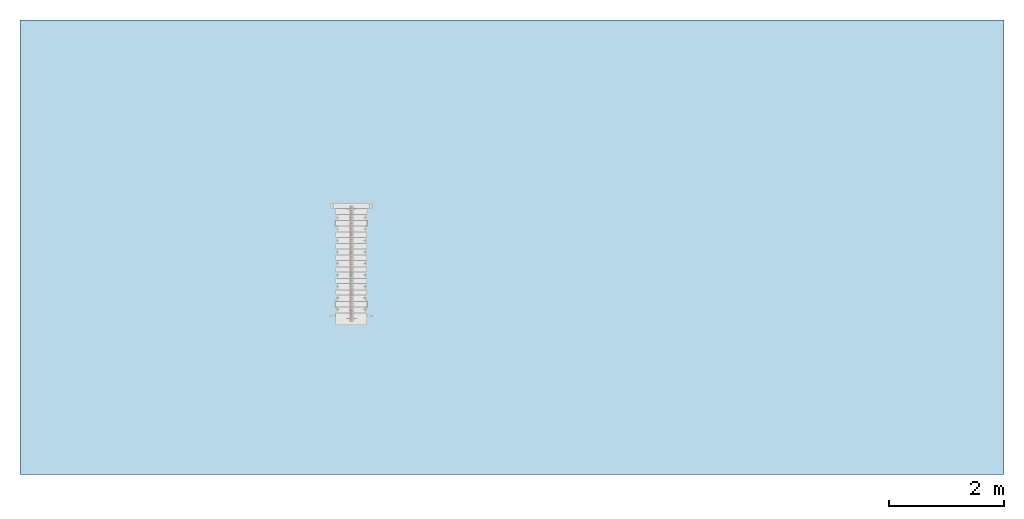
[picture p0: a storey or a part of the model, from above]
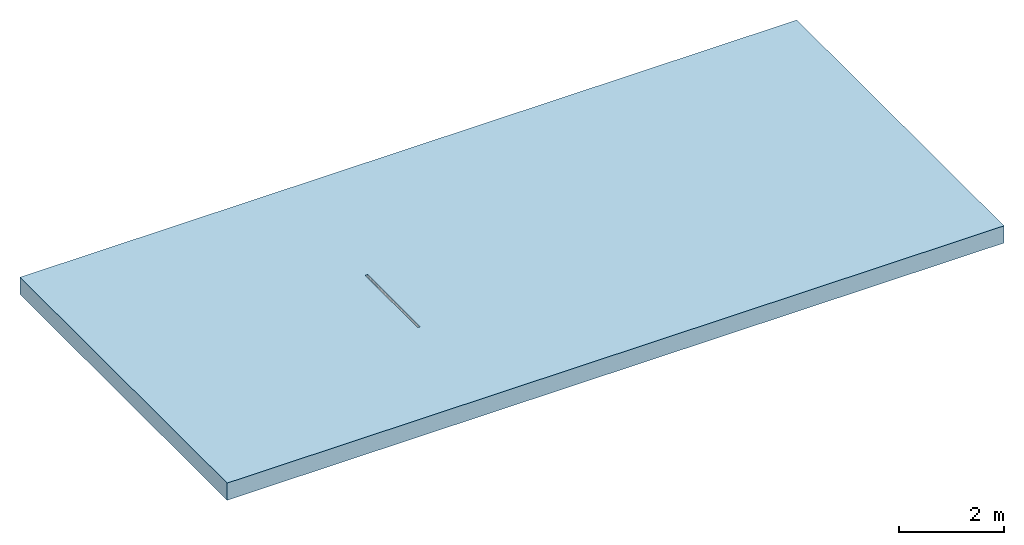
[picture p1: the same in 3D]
Properties of the parts of a building model (IFC2X3)

# File
Description: ViewDefinition [CoordinationView]
File name: 32833 - Q-Guard Edge - G.S.ifc
Time: 2013-07-11T16:58:51
Written by: Autodesk Revit 2013
Made in: 20120221_2030(x64)

# IfcProject, Project Number
LongName: Project Name; Phase: Project Status

# IfcSite, Default
RefLatitude: 42, 21, 30, 344238; RefLongitude: -71, -3, -35, -194702; RefElevation: 0 mm

# IfcBuilding
Pset_BuildingCommon - NumberOfStoreys: 1
Other - Project Name: Project Name; Project Number: Project Number; Client Name: Owner; Project Issue Date: Issue Date; Project Status: Project Status; Project Address: ## Street City, State Zip

# IfcBuildingStorey, Level 1
LongName: Level 1; Elevation: 0 mm
Constraints - Elevation Base: 0; Elevation: 0 mm
Graphics - Color: 0; Symbol at End 1 Default: no; Line Pattern: Center; Symbol at End 2 Default: yes; Symbol: M_Level Head - Circle: M_Level Head - Circle; Line Weight: 1
Dimensions - Computation Height: 0 mm
Identity Data - Structural: no; Name: Level 1; Building Story: yes

# IfcFlowTerminal: 32833 - Q-Guard Edge - G.S, Qmax 700:32833 - Q-Guard Edge - G.S:32833 - Q-Guard Edge - G.S:502881
In: Level 1
Construction - 32854_Chamber connector (at Female end): no; 32882_550-700 Step Connector: no; 32835_Closing End cap (at Female end): no; 32854_Chamber connector (at Male end): no; 32835_Closing End cap (at Male end): yes; E5-QSlot-GalvSteel: no; E3-QFlow-GalvSteel: no; E1-QFlow-DuctileIron: no; E4-QGuard-GalvSteel: yes; E2-QGuard-DuctileIron: no; V_CoarseE1: yes; V_Coarse_E5: no
Identity Data - Mark: 37; Product Brochure: http://www.aco.co.uk/download.php?id=220; URL: www.aco.co.uk; Installation Guidelines: http://www.aco.co.uk/download.php?id=220; Assembly Description: Rain Water Drainage; Type Comments: ACO Qmax 700 channel assembly complete with ACO Q-Guard galvanised steel edge rail; Manufacturer: ACO Technologies plc - ACO Water Management Division; Fax: +44 (0)1462 815895; Maintenance Guidelines: http://www.aco.co.uk/download.php?id=220; e-mail Sales: customersupport@aco.co.uk; Product Page URL: http://www.aco.co.uk/product_detail.php?id=79; OmniClass Title: Rainwater Removal; Model Description: High capacity slot drainage channel system; Cost: 0; Price: POA - contact ACO; Product Code: 32833; Assembly Code: D2040; Address: ACO Business Park, Hitchin Road, Shefford, Bedfordshire, United Kingdom SG17 5TE; OmniClass Number: 23.70.50.24; Model: ACO Qmax 700; e-mail Technical: technical@aco.co.uk; Telephone: +44 (0)1462 816666
Constraints - Moves With Nearby Elements: no; Level: Level: Level 1
Phasing - Phase Created: New Construction
General - TagNumber: 0; SerialNumber: 0
Data - Installation - Reinforcement Details: Refer to brochure; Concrete Surround Volume - Load Class A 15 - D 400: 0.56 m³/m; Concrete Surround Volume - Load Class E 600 - F 900: 0.72 m³/m; Channel C.S.A: 249703mm²; Load Class: A 15 - F 900; ACO Hydraulic Design Software: http://www.acodesign.co.uk; Product Weight: 39.4 kg; Drainage Slot Width: 10mm; Invert Depth: 950mm; Hydraulic Performance: http://www.aco.co.uk/download.php?id=220; Product Standard: BS EN 1433:2002 CE marked; Installation - Concrete Grade: Refer to brochure; Drainage Slot Intake Area: 8356mm²/m; Product Dimensions: 2000mm x 730mm x 1070mm (LxWxH)
Model Properties - 550-700 Step Connector Product Code: 32882; 550-700 Step Connector Weight: 2.5 kg; Chamber Connector Channel Colour: Black; Chamber Connector Model Description: High capacity slot drainage channel system; Closing End Cap Dimensions: 730mm x 12mm x 865mm (LxWxH); Chamber Connector Product Code: 32854; Closing End Cap Material: High Density Polyethylene; 550-700 Step Connector Recyclable: Fully recyclable; Closing End Cap Recycled Material Content: 0%; Chamber Connector Weight: 15.8 kg; Closing End Cap Product Code: 32835; 550-700 Step Connector Recycled Material Content: 0%; Chamber Connector Dimensions: Female End=800mm x 715mm x 895mm, Male End=800mm x 715mm x 845mm (LxWxH); 550-700 Step Connector Model Description: High capacity slot drainage channel system; Closing End Cap Colour: Black; 550-700 Step Connector Material: High Density Polyethylene; Closing End Cap Weight: 4.9 kg; Chamber Connector Recycled Material Content: Variable %; Chamber Connector Recyclable: Fully recyclable; Chamber Connector Channel Material: Medium Density Polyethylene; 550-700 Step Connector Colour: Black; Closing End Cap Recyclable: Fully recyclable; Closing End Cap Model Description: High capacity slot drainage channel system; 550-700 Step Connector Dimensions: 730mm x 45mm x 865mm (LxWxH)
Materials and Finishes - Edge Rail Finish: Galvanised; Channel Colour: Black; Seal Material: EPDM; Edge Rail Colour: Silver; Channel Material: Medium Density Polyethylene; Edge Rail Material: Steel; Seal Colour: Black
Green Building Properties - Channel Recycled Material Content: Variable %; Channel Recyclable: Fully recyclable; Seal Recyclable: Fully recyclable; Edge Rail Recycled Material Content: Between 40% - 90%; Edge Rail Recyclable: Fully recyclable; Seal Recycled Material Content: 0%
Dimensions - StepConn-Origin: 580.3 mm; ClosingEndCapOrigin: 570.2 mm; ChamberOrigin: 480 mm; Floor Opening Width: 55 mm; Length: 2000 mm; Depth Overall: 1070 mm; Width Overall: 730 mm
Other - Revision: 1; Created by: www.aco.co.uk

# IfcOpeningElement: Opening
In: Level 1
Constraints - Height Offset From Level: 0 mm; Level: Level: Level 1; Room Bounding: yes; Related to Mass: no
Dimensions - Perimeter: 50000 mm; Thickness: 400 mm; Volume: 53488000000 mm3; Area: 134980000 mm2
Phasing - Phase Created: New Construction
Structural - Enable Analytical Model: no; Structural: no
Graphics - Coarse Scale Fill Color: 0
Analytical Properties - Absorptance: 0.1; Roughness: 1
Construction - Default Thickness: 400 mm; Function: 0
Materials and Finishes - Structural Material: Plant

# IfcSlab: Floor:Generic Floor - 400mm, Floor:Generic Floor - 400mm:193825
In: Level 1
PredefinedType: FLOOR; Material: Plant 400 mm
Constraints - Height Offset From Level: 0 mm; Level: Level: Level 1; Room Bounding: yes; Related to Mass: no
Dimensions - Perimeter: 50000 mm; Thickness: 400 mm; Volume: 53488000000 mm3; Area: 134980000 mm2
Phasing - Phase Created: New Construction
Structural - Enable Analytical Model: no; Structural: no
Pset_SlabCommon - Reference: Generic Floor - 400mm; IsExternal: no; LoadBearing: yes
Graphics - Coarse Scale Fill Color: 0
Analytical Properties - Absorptance: 0.1; Roughness: 1
Construction - Default Thickness: 400 mm; Function: 0
Materials and Finishes - Structural Material: Plant
